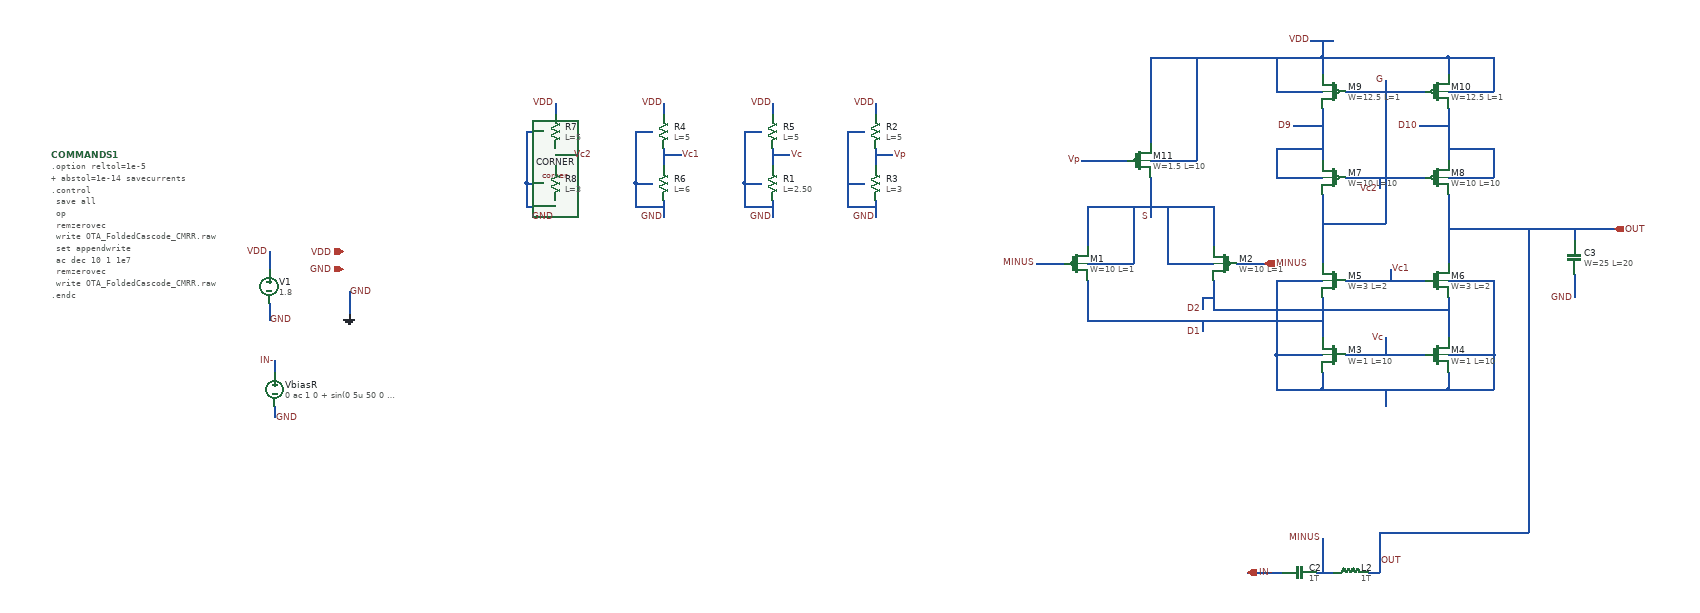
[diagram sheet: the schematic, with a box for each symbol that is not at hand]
v {xschem version=3.4.5 file_version=1.2
}
G {}
K {}
V {}
S {}
E {}
B 2 1500 -250 2050 0 {flags=graph,unlocked


ypos1=0
ypos2=2

subdivy=1
unity=1



subdivx=8
node="\\"out db20()\\""
color=4
dataset=0
unitx=1
logx=1
logy=0

sweep=""
rawfile=$netlist_dir/OTA_FoldedCascode_CMRR.raw
sim_type=ac


y2=0



x2=7
divx=8
divy=10

x1=-5.5511151e-17
y1=-200}
B 2 1500 -500 2050 -250 {flags=graph,unlocked
rawfile=$netlist_dir/OTA_FoldedCascode_CMRR.raw
sim_type=ac
y1=-200
y2=200
ypos1=0
ypos2=2

subdivy=1
unity=1

x2=7

subdivx=8
node=ph(out)
color=4
dataset=0
unitx=1
logx=1
logy=0
divx=8
sweep=""
divy=15
x1=0}
N -990 -270 -990 -230 {
lab=GND}
N -1130 -250 -1130 -220 {
lab=GND}
N -1130 -340 -1130 -310 {
lab=VDD}
N -1120 -70 -1120 -50 {
lab=GND}
N -1120 -150 -1120 -130 {
lab=IN-}
N 580 220 640 220 {
lab=IN-}
N 700 220 730 220 {
lab=MINUS}
N 790 220 810 220 {
lab=OUT}
N 810 150 810 220 {
lab=OUT}
N 710 160 710 200 {
lab=MINUS}
N 710 200 710 220 {
lab=MINUS}
N -70 -600 -70 -580 {
lab=VDD}
N -70 -430 -70 -400 {
lab=GND}
N -70 -520 -70 -490 {
lab=Vp}
N -70 -510 -40 -510 {
lab=Vp}
N -100 -550 -90 -550 {
lab=GND}
N -120 -550 -120 -420 {
lab=GND}
N -100 -420 -70 -420 {
lab=GND}
N -100 -460 -90 -460 {
lab=GND}
N -120 -550 -100 -550 {
lab=GND}
N -120 -460 -100 -460 {
lab=GND}
N -120 -420 -100 -420 {
lab=GND}
N -250 -600 -250 -580 {
lab=VDD}
N -250 -520 -250 -490 {
lab=Vc}
N -250 -430 -250 -400 {
lab=GND}
N -250 -510 -220 -510 {
lab=Vc}
N -300 -460 -270 -460 {
lab=GND}
N -300 -460 -300 -420 {
lab=GND}
N -300 -420 -250 -420 {
lab=GND}
N -300 -550 -270 -550 {
lab=GND}
N -300 -550 -300 -460 {
lab=GND}
N -440 -600 -440 -580 {
lab=VDD}
N -440 -520 -440 -490 {
lab=Vc1}
N -440 -430 -440 -400 {
lab=GND}
N -440 -510 -410 -510 {
lab=Vc1}
N -490 -460 -460 -460 {
lab=GND}
N -490 -460 -490 -420 {
lab=GND}
N -490 -420 -440 -420 {
lab=GND}
N -490 -550 -460 -550 {
lab=GND}
N -490 -550 -490 -460 {
lab=GND}
N -630 -600 -630 -580 {
lab=VDD}
N -630 -520 -630 -490 {
lab=Vc2}
N -630 -430 -630 -400 {
lab=GND}
N -630 -510 -600 -510 {
lab=Vc2}
N -680 -460 -650 -460 {
lab=GND}
N -680 -460 -680 -420 {
lab=GND}
N -680 -420 -630 -420 {
lab=GND}
N -680 -550 -650 -550 {
lab=GND}
N -680 -550 -680 -460 {
lab=GND}
N 690 -710 730 -710 {
lab=VDD}
N 750 -160 890 -160 {
lab=Vc}
N 710 -130 710 -100 {
lab=#net1}
N 710 -100 930 -100 {
lab=#net1}
N 930 -130 930 -100 {
lab=#net1}
N 710 -260 710 -190 {
lab=D1}
N 930 -260 930 -190 {
lab=D2}
N 750 -290 890 -290 {
lab=Vc1}
N 710 -440 710 -320 {
lab=G}
N 930 -440 930 -320 {
lab=OUT}
N 750 -470 890 -470 {
lab=Vc2}
N 710 -590 710 -500 {
lab=D9}
N 930 -590 930 -500 {
lab=D10}
N 710 -680 710 -650 {
lab=VDD}
N 710 -680 930 -680 {
lab=VDD}
N 930 -680 930 -650 {
lab=VDD}
N 750 -620 890 -620 {
lab=G}
N 520 -240 930 -240 {
lab=D2}
N 520 -290 520 -240 {
lab=D2}
N 640 -220 710 -220 {
lab=D1}
N 620 -220 640 -220 {
lab=D1}
N 300 -220 620 -220 {
lab=D1}
N 300 -290 300 -220 {
lab=D1}
N 560 -320 610 -320 {
lab=MINUS}
N 210 -320 260 -320 {
lab=#net2}
N 930 -380 1030 -380 {
lab=OUT}
N 300 -420 300 -350 {
lab=S}
N 520 -420 520 -350 {
lab=S}
N 300 -420 520 -420 {
lab=S}
N 410 -470 410 -420 {
lab=S}
N 410 -680 690 -680 {
lab=VDD}
N 410 -680 410 -670 {
lab=VDD}
N 690 -680 710 -680 {
lab=VDD}
N 710 -390 820 -390 {
lab=G}
N 820 -620 820 -390 {
lab=G}
N 440 -320 520 -320 {
lab=S}
N 440 -420 440 -320 {
lab=S}
N 300 -320 380 -320 {
lab=S}
N 380 -420 380 -320 {
lab=S}
N 630 -160 710 -160 {
lab=#net1}
N 630 -160 630 -100 {
lab=#net1}
N 630 -100 710 -100 {
lab=#net1}
N 930 -160 1010 -160 {
lab=#net1}
N 1010 -160 1010 -100 {
lab=#net1}
N 930 -100 1010 -100 {
lab=#net1}
N 930 -290 1010 -290 {
lab=#net1}
N 1010 -290 1010 -240 {
lab=#net1}
N 630 -290 710 -290 {
lab=#net1}
N 630 -290 630 -250 {
lab=#net1}
N 930 -470 1000 -470 {
lab=D10}
N 1000 -470 1010 -470 {
lab=D10}
N 1010 -520 1010 -470 {
lab=D10}
N 930 -520 1010 -520 {
lab=D10}
N 630 -470 710 -470 {
lab=D9}
N 630 -520 630 -470 {
lab=D9}
N 630 -520 710 -520 {
lab=D9}
N 630 -620 710 -620 {
lab=VDD}
N 630 -680 630 -620 {
lab=VDD}
N 930 -620 1010 -620 {
lab=VDD}
N 1010 -680 1010 -620 {
lab=VDD}
N 930 -680 1010 -680 {
lab=VDD}
N 830 -310 830 -290 {
lab=Vc1}
N 820 -190 820 -160 {
lab=Vc}
N 810 -470 810 -450 {
lab=Vc2}
N 500 -220 500 -200 {
lab=D1}
N 500 -260 500 -240 {
lab=D2}
N 500 -260 520 -260 {
lab=D2}
N 820 -640 820 -620 {
lab=G}
N 880 -560 930 -560 {
lab=D10}
N 660 -560 710 -560 {
lab=D9}
N 410 -420 410 -400 {
lab=S}
N 820 -100 820 -70 {
lab=#net1}
N 710 -710 710 -680 {
lab=VDD}
N 630 -250 630 -160 {
lab=#net1}
N 1010 -240 1010 -160 {
lab=#net1}
N 410 -670 410 -620 {
lab=VDD}
N 410 -620 410 -530 {
lab=VDD}
N 1030 -380 1220 -380 {
lab=OUT}
N 1070 -380 1070 -350 {
lab=OUT}
N 1150 -380 1150 -360 {
lab=OUT}
N 1150 -300 1150 -260 {
lab=GND}
N 410 -500 490 -500 {
lab=VDD}
N 290 -500 370 -500 {
lab=Vp}
N 490 -680 490 -500 {
lab=VDD}
N 1070 -350 1070 150 {
lab=OUT}
N 810 150 1070 150 {
lab=OUT}
C {devices/iopin.sym} -1000 -340 0 0 {name=p1 lab=VDD}
C {devices/iopin.sym} -1000 -310 0 0 {name=p2 lab=GND}
C {devices/ipin.sym} 580 220 2 1 {name=p4 lab=IN-}
C {devices/vsource.sym} -1130 -280 0 0 {name=V1 value=1.8 savecurrent=false}
C {devices/gnd.sym} -990 -230 0 0 {name=l1 lab=GND}
C {devices/lab_pin.sym} -990 -270 0 1 {name=p8 sig_type=std_logic lab=GND}
C {devices/lab_pin.sym} -1130 -220 0 1 {name=p9 sig_type=std_logic lab=GND}
C {devices/lab_pin.sym} -1130 -340 0 0 {name=p10 sig_type=std_logic lab=VDD}
C {devices/vsource.sym} -1120 -100 0 0 {name=VbiasR value="0 ac 1 0
+ sin(0 5u 50 0 0 0)"}
C {devices/lab_pin.sym} -1120 -150 0 0 {name=p13 sig_type=std_logic lab=IN-}
C {devices/launcher.sym} 1710 -610 0 0 {name=h1
descr="Annotate OP" 
tclcommand="set show_hidden_texts 1; xschem annotate_op"
}
C {devices/lab_pin.sym} -1120 -50 0 1 {name=p12 sig_type=std_logic lab=GND}
C {devices/simulator_commands_shown.sym} -1510 -510 0 0 {name=COMMANDS1
simulator=ngspice
only_toplevel=false 
value="
.option reltol=1e-5
+  abstol=1e-14 savecurrents
.control
  save all
  op
  remzerovec 
  write OTA_FoldedCascode_CMRR.raw

  set appendwrite
  ac dec 10 1 1e7
  remzerovec
  write OTA_FoldedCascode_CMRR.raw

.endc
"}
C {devices/launcher.sym} 1710 -660 0 0 {name=h3
descr="Netlist & sim" 
tclcommand="xschem netlist; xschem simulate"}
C {devices/launcher.sym} 1710 -550 0 0 {name=h4 
descr="Load/unload
AC waveforms" 
tclcommand="
xschem raw_read $netlist_dir/OTA_FoldedCascode_AC.raw ac
"
}
C {sky130_fd_pr/corner.sym} -1160 -530 0 0 {name=CORNER only_toplevel=true corner=tt}
C {devices/capa.sym} 670 220 1 1 {name=C2
m=1
value=1T
footprint=1206
device="ceramic capacitor"}
C {devices/ind.sym} 760 220 1 1 {name=L2
m=1
value=1T
footprint=1206
device=inductor}
C {devices/lab_pin.sym} 810 200 2 0 {name=l3 sig_type=std_logic lab=OUT}
C {devices/lab_pin.sym} 710 160 2 1 {name=l4 sig_type=std_logic lab=MINUS}
C {devices/launcher.sym} -160 -190 0 0 {name=h2
descr="Annotate OP" 
tclcommand="set show_hidden_texts 1; xschem annotate_op"
}
C {devices/launcher.sym} -160 -240 0 0 {name=h5
descr="Netlist & sim" 
tclcommand="xschem netlist; xschem simulate"}
C {devices/lab_pin.sym} -70 -400 0 0 {name=p38 sig_type=std_logic lab=GND}
C {devices/lab_pin.sym} -70 -600 0 0 {name=p39 sig_type=std_logic lab=VDD}
C {devices/lab_pin.sym} -40 -510 0 1 {name=p34 sig_type=std_logic lab=Vp}
C {devices/lab_pin.sym} -250 -600 0 0 {name=p36 sig_type=std_logic lab=VDD}
C {devices/lab_pin.sym} -250 -400 0 0 {name=p37 sig_type=std_logic lab=GND}
C {devices/lab_pin.sym} -220 -510 0 1 {name=p18 sig_type=std_logic lab=Vc}
C {sky130_fd_pr/res_xhigh_po_0p35.sym} -250 -550 0 0 {name=R5
L=5
model=res_xhigh_po_0p35
spiceprefix=X
mult=1}
C {sky130_fd_pr/res_xhigh_po_0p35.sym} -250 -460 0 0 {name=R1
L=2.50
model=res_xhigh_po_0p35
spiceprefix=X
mult=1}
C {sky130_fd_pr/res_xhigh_po_0p35.sym} -70 -550 0 0 {name=R2
L=5
model=res_xhigh_po_0p35
spiceprefix=X
mult=1}
C {sky130_fd_pr/res_xhigh_po_0p35.sym} -70 -460 0 0 {name=R3
L=3
model=res_xhigh_po_0p35
spiceprefix=X
mult=1}
C {devices/lab_pin.sym} -440 -600 0 0 {name=p19 sig_type=std_logic lab=VDD}
C {devices/lab_pin.sym} -440 -400 0 0 {name=p20 sig_type=std_logic lab=GND}
C {devices/lab_pin.sym} -410 -510 0 1 {name=p21 sig_type=std_logic lab=Vc1}
C {sky130_fd_pr/res_xhigh_po_0p35.sym} -440 -550 0 0 {name=R4
L=5
model=res_xhigh_po_0p35
spiceprefix=X
mult=1}
C {sky130_fd_pr/res_xhigh_po_0p35.sym} -440 -460 0 0 {name=R6
L=6
model=res_xhigh_po_0p35
spiceprefix=X
mult=1}
C {devices/lab_pin.sym} -630 -600 0 0 {name=p22 sig_type=std_logic lab=VDD}
C {devices/lab_pin.sym} -630 -400 0 0 {name=p23 sig_type=std_logic lab=GND}
C {devices/lab_pin.sym} -600 -510 0 1 {name=p30 sig_type=std_logic lab=Vc2}
C {sky130_fd_pr/res_xhigh_po_0p35.sym} -630 -550 0 0 {name=R7
L=5
model=res_xhigh_po_0p35
spiceprefix=X
mult=1}
C {sky130_fd_pr/res_xhigh_po_0p35.sym} -630 -460 0 0 {name=R8
L=3
model=res_xhigh_po_0p35
spiceprefix=X
mult=1}
C {devices/ipin.sym} 610 -320 0 1 {name=p17 lab=MINUS}
C {devices/opin.sym} 1220 -380 0 0 {name=p24 lab=OUT}
C {devices/lab_wire.sym} 690 -710 0 0 {name=p25 sig_type=std_logic lab=VDD}
C {sky130_fd_pr/pfet_01v8.sym} 280 -320 0 0 {name=M1
L=1
W=10
nf=1
mult=5
ad="'int((nf+1)/2) * W/nf * 0.29'" 
pd="'2*int((nf+1)/2) * (W/nf + 0.29)'"
as="'int((nf+2)/2) * W/nf * 0.29'" 
ps="'2*int((nf+2)/2) * (W/nf + 0.29)'"
nrd="'0.29 / W'" nrs="'0.29 / W'"
sa=0 sb=0 sd=0
model=pfet_01v8
spiceprefix=X
}
C {sky130_fd_pr/pfet_01v8.sym} 540 -320 0 1 {name=M2
L=1
W=10
nf=1
mult=5
ad="'int((nf+1)/2) * W/nf * 0.29'" 
pd="'2*int((nf+1)/2) * (W/nf + 0.29)'"
as="'int((nf+2)/2) * W/nf * 0.29'" 
ps="'2*int((nf+2)/2) * (W/nf + 0.29)'"
nrd="'0.29 / W'" nrs="'0.29 / W'"
sa=0 sb=0 sd=0
model=pfet_01v8
spiceprefix=X
}
C {sky130_fd_pr/nfet_01v8.sym} 730 -160 0 1 {name=M3
L=10
W=1
nf=1 
mult=1
ad="'int((nf+1)/2) * W/nf * 0.29'" 
pd="'2*int((nf+1)/2) * (W/nf + 0.29)'"
as="'int((nf+2)/2) * W/nf * 0.29'" 
ps="'2*int((nf+2)/2) * (W/nf + 0.29)'"
nrd="'0.29 / W'" nrs="'0.29 / W'"
sa=0 sb=0 sd=0
model=nfet_01v8
spiceprefix=X
}
C {sky130_fd_pr/nfet_01v8.sym} 910 -160 0 0 {name=M4
L=10
W=1
nf=1 
mult=1
ad="'int((nf+1)/2) * W/nf * 0.29'" 
pd="'2*int((nf+1)/2) * (W/nf + 0.29)'"
as="'int((nf+2)/2) * W/nf * 0.29'" 
ps="'2*int((nf+2)/2) * (W/nf + 0.29)'"
nrd="'0.29 / W'" nrs="'0.29 / W'"
sa=0 sb=0 sd=0
model=nfet_01v8
spiceprefix=X
}
C {sky130_fd_pr/nfet_01v8.sym} 730 -290 0 1 {name=M5
L=2
W=3
nf=1 
mult=1
ad="'int((nf+1)/2) * W/nf * 0.29'" 
pd="'2*int((nf+1)/2) * (W/nf + 0.29)'"
as="'int((nf+2)/2) * W/nf * 0.29'" 
ps="'2*int((nf+2)/2) * (W/nf + 0.29)'"
nrd="'0.29 / W'" nrs="'0.29 / W'"
sa=0 sb=0 sd=0
model=nfet_01v8
spiceprefix=X
}
C {sky130_fd_pr/nfet_01v8.sym} 910 -290 0 0 {name=M6
L=2
W=3
nf=1 
mult=1
ad="'int((nf+1)/2) * W/nf * 0.29'" 
pd="'2*int((nf+1)/2) * (W/nf + 0.29)'"
as="'int((nf+2)/2) * W/nf * 0.29'" 
ps="'2*int((nf+2)/2) * (W/nf + 0.29)'"
nrd="'0.29 / W'" nrs="'0.29 / W'"
sa=0 sb=0 sd=0
model=nfet_01v8
spiceprefix=X
}
C {sky130_fd_pr/pfet_01v8.sym} 730 -470 0 1 {name=M7
L=10
W=10
nf=1
mult=1
ad="'int((nf+1)/2) * W/nf * 0.29'" 
pd="'2*int((nf+1)/2) * (W/nf + 0.29)'"
as="'int((nf+2)/2) * W/nf * 0.29'" 
ps="'2*int((nf+2)/2) * (W/nf + 0.29)'"
nrd="'0.29 / W'" nrs="'0.29 / W'"
sa=0 sb=0 sd=0
model=pfet_01v8
spiceprefix=X
}
C {sky130_fd_pr/pfet_01v8.sym} 910 -470 0 0 {name=M8
L=10
W=10
nf=1
mult=1
ad="'int((nf+1)/2) * W/nf * 0.29'" 
pd="'2*int((nf+1)/2) * (W/nf + 0.29)'"
as="'int((nf+2)/2) * W/nf * 0.29'" 
ps="'2*int((nf+2)/2) * (W/nf + 0.29)'"
nrd="'0.29 / W'" nrs="'0.29 / W'"
sa=0 sb=0 sd=0
model=pfet_01v8
spiceprefix=X
}
C {sky130_fd_pr/pfet_01v8.sym} 730 -620 0 1 {name=M9
L=1
W=12.5
nf=1
mult=1
ad="'int((nf+1)/2) * W/nf * 0.29'" 
pd="'2*int((nf+1)/2) * (W/nf + 0.29)'"
as="'int((nf+2)/2) * W/nf * 0.29'" 
ps="'2*int((nf+2)/2) * (W/nf + 0.29)'"
nrd="'0.29 / W'" nrs="'0.29 / W'"
sa=0 sb=0 sd=0
model=pfet_01v8
spiceprefix=X
}
C {sky130_fd_pr/pfet_01v8.sym} 910 -620 0 0 {name=M10
L=1
W=12.5
nf=1
mult=1
ad="'int((nf+1)/2) * W/nf * 0.29'" 
pd="'2*int((nf+1)/2) * (W/nf + 0.29)'"
as="'int((nf+2)/2) * W/nf * 0.29'" 
ps="'2*int((nf+2)/2) * (W/nf + 0.29)'"
nrd="'0.29 / W'" nrs="'0.29 / W'"
sa=0 sb=0 sd=0
model=pfet_01v8
spiceprefix=X
}
C {devices/lab_pin.sym} 500 -200 0 0 {name=p27 sig_type=std_logic lab=D1}
C {devices/lab_pin.sym} 500 -240 0 0 {name=p28 sig_type=std_logic lab=D2

}
C {devices/lab_pin.sym} 820 -640 0 0 {name=p29 sig_type=std_logic lab=G

}
C {devices/lab_pin.sym} 880 -560 0 0 {name=p31 sig_type=std_logic lab=D10

}
C {devices/lab_pin.sym} 660 -560 0 0 {name=p32 sig_type=std_logic lab=D9

}
C {devices/lab_pin.sym} 410 -400 0 0 {name=p33 sig_type=std_logic lab=S

}
C {devices/lab_pin.sym} 820 -190 0 0 {name=p35 sig_type=std_logic lab=Vc}
C {devices/lab_pin.sym} 830 -310 0 1 {name=p40 sig_type=std_logic lab=Vc1}
C {devices/lab_pin.sym} 810 -450 0 0 {name=p41 sig_type=std_logic lab=Vc2}
C {devices/lab_wire.sym} 1150 -260 0 0 {name=p42 sig_type=std_logic lab=GND}
C {sky130_fd_pr/cap_mim_m3_1.sym} 1150 -330 0 0 {name=C3 model=cap_mim_m3_1 W=25 L=20 MF=1 spiceprefix=X}
C {sky130_fd_pr/pfet_01v8.sym} 390 -500 0 0 {name=M11
L=10
W=1.5
nf=1
mult=1
ad="'int((nf+1)/2) * W / nf * 0.29'"
pd="'2*int((nf+1)/2) * (W / nf + 0.29)'"
as="'int((nf+2)/2) * W / nf * 0.29'"
ps="'2*int((nf+2)/2) * (W / nf + 0.29)'"
nrd="'0.29 / W '" nrs="'0.29 / W '"
sa=0 sb=0 sd=0
model=pfet_01v8
spiceprefix=X
}
C {devices/lab_pin.sym} 290 -500 0 0 {name=p43 sig_type=std_logic lab=Vp}
C {devices/lab_pin.sym} 210 -320 2 1 {name=l5 sig_type=std_logic lab=MINUS}
